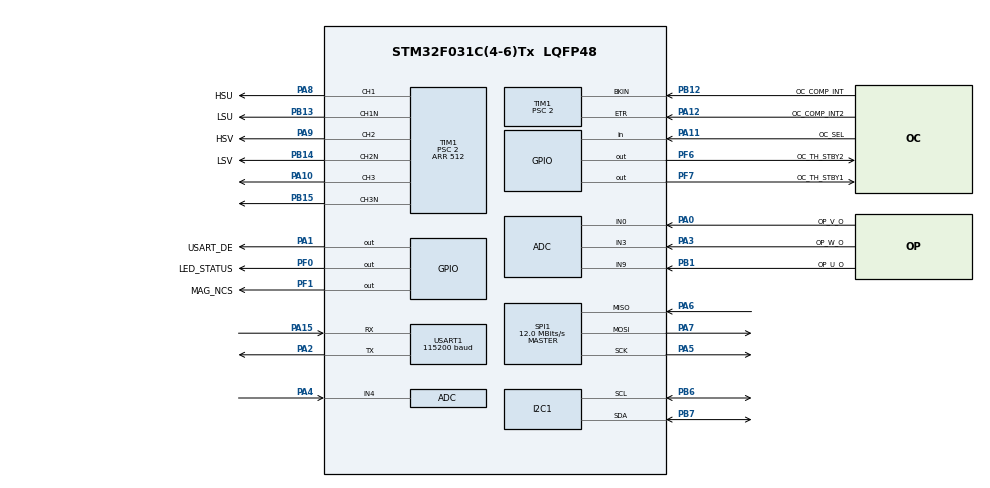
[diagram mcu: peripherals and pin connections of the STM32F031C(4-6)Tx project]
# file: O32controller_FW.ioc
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Dma.ADC.0.Direction=DMA_PERIPH_TO_MEMORY
Dma.ADC.0.Instance=DMA1_Channel1
Dma.ADC.0.MemDataAlignment=DMA_MDATAALIGN_HALFWORD
Dma.ADC.0.MemInc=DMA_MINC_ENABLE
Dma.ADC.0.Mode=DMA_CIRCULAR
Dma.ADC.0.PeriphDataAlignment=DMA_PDATAALIGN_HALFWORD
Dma.ADC.0.PeriphInc=DMA_PINC_DISABLE
Dma.ADC.0.Priority=DMA_PRIORITY_MEDIUM
Dma.Request0=ADC
Dma.Request1=USART1_TX
Dma.USART1_TX.1.Direction=DMA_MEMORY_TO_PERIPH
Dma.USART1_TX.1.Instance=DMA1_Channel4
Dma.USART1_TX.1.MemDataAlignment=DMA_MDATAALIGN_BYTE
Dma.USART1_TX.1.MemInc=DMA_MINC_ENABLE
Dma.USART1_TX.1.Mode=DMA_NORMAL
Dma.USART1_TX.1.PeriphDataAlignment=DMA_PDATAALIGN_BYTE
Dma.USART1_TX.1.PeriphInc=DMA_PINC_DISABLE
Dma.USART1_TX.1.Priority=DMA_PRIORITY_LOW
I2C1.NoStretchMode=I2C_NOSTRETCH_DISABLE
I2C1.OwnAddress=9
Mcu.Family=STM32F0
Mcu.Name=STM32F031C(4-6)Tx
Mcu.Package=LQFP48
NVIC.DMA1_Channel1_IRQn=true\:0\:0\:false\:false\:true\:false\:true\:true
NVIC.DMA1_Channel4_5_IRQn=true\:0\:0\:false\:false\:true\:false\:true\:true
NVIC.I2C1_IRQn=true\:0\:0\:false\:false\:true\:true\:true\:true
NVIC.SPI1_IRQn=true\:0\:0\:false\:false\:true\:true\:true\:true
NVIC.TIM2_IRQn=true\:0\:0\:false\:false\:true\:true\:true\:true
NVIC.USART1_IRQn=true\:0\:0\:false\:false\:true\:true\:true\:true
PA0.GPIO_Label=OP_V_O
PA0.Mode=IN0
PA0.Signal=ADC_IN0
PA1.GPIO_Label=USART_DE
PA1.GPIO_PuPd=GPIO_PULLDOWN
PA1.Signal=GPIO_Output
PA10.Signal=S_TIM1_CH3
PA11.GPIO_Label=OC_SEL
PA11.Signal=GPIO_Input
PA12.GPIO_Label=OC_COMP_INT2
PA12.Signal=S_TIM1_ETR
PA13.Mode=Serial_Wire
PA13.Signal=SYS_SWDIO
PA14.Mode=Serial_Wire
PA14.Signal=SYS_SWCLK
PA15.Mode=Asynchronous
PA15.Signal=USART1_RX
PA2.Mode=Asynchronous
PA2.Signal=USART1_TX
PA3.GPIO_Label=OP_W_O
PA3.Signal=SharedAnalog_PA3
PA4.Mode=IN4
PA4.Signal=ADC_IN4
PA5.Mode=Full_Duplex_Master
PA5.Signal=SPI1_SCK
PA6.Mode=Full_Duplex_Master
PA6.Signal=SPI1_MISO
PA7.Mode=Full_Duplex_Master
PA7.Signal=SPI1_MOSI
PA8.GPIO_Label=HSU
PA8.Signal=S_TIM1_CH1
PA9.GPIO_Label=HSV
PA9.Signal=S_TIM1_CH2
PB1.GPIO_Label=OP_U_O
PB1.Signal=SharedAnalog_PB1
PB12.GPIO_Label=OC_COMP_INT
PB12.Mode=Activate-Break-Input
PB12.Signal=TIM1_BKIN
PB13.GPIO_Label=LSU
PB13.Mode=PWM Generation1 CH1 CH1N
PB13.Signal=TIM1_CH1N
PB14.GPIO_Label=LSV
PB14.Mode=PWM Generation2 CH2 CH2N
PB14.Signal=TIM1_CH2N
PB15.Mode=PWM Generation3 CH3 CH3N
PB15.Signal=TIM1_CH3N
PB6.Mode=I2C
PB6.Signal=I2C1_SCL
PB7.Mode=I2C
PB7.Signal=I2C1_SDA
PF0-OSC_IN.GPIO_Label=LED_STATUS
PF0-OSC_IN.Signal=GPIO_Output
PF1-OSC_OUT.GPIO_Label=MAG_NCS
PF1-OSC_OUT.Signal=GPIO_Output
PF6.GPIO_Label=OC_TH_STBY2
PF6.Signal=GPIO_Output
PF7.GPIO_Label=OC_TH_STBY1
PF7.Signal=GPIO_Output
ProjectManager.HeapSize=0x200
ProjectManager.StackSize=0x400
ProjectManager.TargetToolchain=STM32CubeIDE
RCC.AHBFreq_Value=48000000
RCC.APB1Freq_Value=48000000
RCC.APB1TimFreq_Value=48000000
RCC.HCLKFreq_Value=48000000
RCC.PLLMUL=RCC_PLL_MUL12
RCC.SYSCLKFreq_VALUE=48000000
RCC.SYSCLKSource=RCC_SYSCLKSOURCE_PLLCLK
SH.S_TIM1_CH1.0=TIM1_CH1,PWM Generation1 CH1 CH1N
SH.S_TIM1_CH2.0=TIM1_CH2,PWM Generation2 CH2 CH2N
SH.S_TIM1_CH3.0=TIM1_CH3,PWM Generation3 CH3 CH3N
SH.S_TIM1_ETR.0=TIM1_ETR,TriggerSource_ETR
SH.SharedAnalog_PA3.0=GPIO_Analog
SH.SharedAnalog_PA3.1=ADC_IN3,IN3
SH.SharedAnalog_PB1.0=GPIO_Analog
SH.SharedAnalog_PB1.1=ADC_IN9,IN9
SPI1.BaudRatePrescaler=SPI_BAUDRATEPRESCALER_4
SPI1.CLKPolarity=SPI_POLARITY_HIGH
SPI1.CalculateBaudRate=12.0 MBits/s
SPI1.DataSize=SPI_DATASIZE_8BIT
SPI1.Direction=SPI_DIRECTION_2LINES
SPI1.Mode=SPI_MODE_MASTER
SPI1.VirtualType=VM_MASTER
TIM1.BreakPolarity=TIM_BREAKPOLARITY_HIGH
TIM1.BreakState=TIM_BREAK_DISABLE
TIM1.Channel-PWM\ Generation1\ CH1\ CH1N=TIM_CHANNEL_1
TIM1.Channel-PWM\ Generation2\ CH2\ CH2N=TIM_CHANNEL_2
TIM1.Channel-PWM\ Generation3\ CH3\ CH3N=TIM_CHANNEL_3
TIM1.DeadTime=10
TIM1.OCIdleState_1=TIM_OCIDLESTATE_RESET
TIM1.OCNIdleState_1=TIM_OCNIDLESTATE_RESET
TIM1.OCNIdleState_2=TIM_OCNIDLESTATE_RESET
TIM1.OCNPolarity_1=TIM_OCNPOLARITY_HIGH
TIM1.OCNPolarity_2=TIM_OCNPOLARITY_HIGH
TIM1.OCPolarity_2=TIM_OCPOLARITY_HIGH
TIM1.Period=512
TIM1.Prescaler=2
TIM1.Pulse-PWM\ Generation1\ CH1\ CH1N=0
TIM1.Slave_TriggerPolarity=TIM_TRIGGERPOLARITY_INVERTED
TIM1.TIM_MasterOutputTrigger=TIM_TRGO_RESET
TIM1.TIM_MasterSlaveMode=TIM_MASTERSLAVEMODE_DISABLE
TIM2.Period=10000
TIM2.Prescaler=63
USART1.BaudRate=115200
USART1.VirtualMode-Asynchronous=VM_ASYNC
VP_ADC_TempSens_Input.Mode=IN-TempSens
VP_ADC_Vref_Input.Mode=IN-Vrefint
VP_TIM1_VS_ClockSourceINT.Mode=Internal
VP_TIM1_VS_ControllerModeGated.Mode=Gated Mode
VP_TIM2_VS_ClockSourceINT.Mode=Internal
board=custom

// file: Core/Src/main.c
/* USER CODE BEGIN Header */

/* USER CODE END Header */
#include "main.h"

/* USER CODE BEGIN Includes */
#include "global.h"

#include "sixstep.h"
#include "foc.h"
#include "encoder.h"

#include <stdio.h>

/* USER CODE END Includes */

ADC_HandleTypeDef hadc;
DMA_HandleTypeDef hdma_adc;

I2C_HandleTypeDef hi2c1;

SPI_HandleTypeDef hspi1;

TIM_HandleTypeDef htim1;
TIM_HandleTypeDef htim2;

UART_HandleTypeDef huart1;
DMA_HandleTypeDef hdma_usart1_tx;

/* USER CODE BEGIN PV */

PeripherialStruct p = {0};

/* USER CODE END PV */

void SystemClock_Config(void);
static void MX_GPIO_Init(void);
static void MX_DMA_Init(void);
static void MX_I2C1_Init(void);
static void MX_ADC_Init(void);
static void MX_SPI1_Init(void);
static void MX_TIM1_Init(void);
static void MX_USART1_UART_Init(void);
static void MX_TIM2_Init(void);
/* USER CODE BEGIN PFP */

// overrides printf
int __io_putchar(int ch) {
    HAL_UART_Transmit(&huart1, (uint8_t *)&ch, 1, HAL_MAX_DELAY);
    return ch;
}

/* USER CODE END PFP */

int main(void) {

    /* MCU Configuration--------------------------------------------------------*/

    /* Reset of all peripherals, Initializes the Flash interface and the Systick. */
    HAL_Init();

    /* Configure the system clock */
    SystemClock_Config();

    /* Initialize all configured peripherals */
    MX_GPIO_Init();
    MX_DMA_Init();
    HAL_Delay(10);
    MX_I2C1_Init();
    MX_ADC_Init();
    MX_SPI1_Init();
    MX_TIM1_Init();
    MX_USART1_UART_Init();
    MX_TIM2_Init();
    /* USER CODE BEGIN 2 */

    HAL_MultiProcessor_Init(&huart1, UART_ADDR, UART_WAKEUPMETHOD_ADDRESSMARK);
    HAL_MultiProcessorEx_AddressLength_Set(&huart1, UART_ADDRESS_DETECT_4B);

    HAL_MultiProcessor_EnableMuteMode(&huart1);
    HAL_MultiProcessor_EnterMuteMode(&huart1);

    DISABLE_DRIVE;
    RS485_SET_RX;

    switch(SELECTED_MODE){
        case SIXSTEP_MODE:
            sixstep_startup();
            break;
        case FOC_MODE:
            foc_startup();
            break;
        case ENCODER_MODE:
            encoder_startup();
            break;
        default:
            break;
    }

    /* USER CODE END 2 */

    /* Infinite loop */
    /* USER CODE BEGIN WHILE */

    while (1) {

        switch(SELECTED_MODE){
        case SIXSTEP_MODE:
            sixstep_loop();
            break;
        case FOC_MODE:
            foc_loop();
            break;
        case ENCODER_MODE:
            encoder_loop();
            break;
        default:
            break;
    }

    if(p.clock_1khz_flag){ //watchdog checks if UART has been updated
        p.clock_1khz_flag = 0;

        switch (SELECTED_MODE) {
        case SIXSTEP_MODE:
            sixstep_slowloop();
            break;
        case FOC_MODE:
            foc_slowloop();
            break;
        case ENCODER_MODE:
            break;
        default:
            break;
        }

        p.uart_watchdog++;
        if (p.uart_watchdog >= UART_WATCHDOG_MS) {
            p.uart_watchdog = UART_WATCHDOG_MS;
            DISABLE_DRIVE;
            LED_RED;
        }
    }

        /* USER CODE END WHILE */

    }
}

void SystemClock_Config(void) {
    RCC_OscInitTypeDef RCC_OscInitStruct = {0};
    RCC_ClkInitTypeDef RCC_ClkInitStruct = {0};
    RCC_PeriphCLKInitTypeDef PeriphClkInit = {0};

    /** Initializes the RCC Oscillators according to the specified parameters
     * in the RCC_OscInitTypeDef structure.
     */
    RCC_OscInitStruct.OscillatorType = RCC_OSCILLATORTYPE_HSI | RCC_OSCILLATORTYPE_HSI14;
    RCC_OscInitStruct.HSIState = RCC_HSI_ON;
    RCC_OscInitStruct.HSI14State = RCC_HSI14_ON;
    RCC_OscInitStruct.HSICalibrationValue = RCC_HSICALIBRATION_DEFAULT;
    RCC_OscInitStruct.HSI14CalibrationValue = 16;
    RCC_OscInitStruct.PLL.PLLState = RCC_PLL_ON;
    RCC_OscInitStruct.PLL.PLLSource = RCC_PLLSOURCE_HSI;
    RCC_OscInitStruct.PLL.PLLMUL = RCC_PLL_MUL16; // can do RCC_PLL_MUL16 for 64MHz clock speed (affects PWM)
    RCC_OscInitStruct.PLL.PREDIV = RCC_PREDIV_DIV1;
    if (HAL_RCC_OscConfig(&RCC_OscInitStruct) != HAL_OK) {
        Error_Handler();
    }

    /** Initializes the CPU, AHB and APB buses clocks
     */
    RCC_ClkInitStruct.ClockType = RCC_CLOCKTYPE_HCLK | RCC_CLOCKTYPE_SYSCLK | RCC_CLOCKTYPE_PCLK1;
    RCC_ClkInitStruct.SYSCLKSource = RCC_SYSCLKSOURCE_PLLCLK;
    RCC_ClkInitStruct.AHBCLKDivider = RCC_SYSCLK_DIV1;
    RCC_ClkInitStruct.APB1CLKDivider = RCC_HCLK_DIV1;

    if (HAL_RCC_ClockConfig(&RCC_ClkInitStruct, FLASH_LATENCY_1) != HAL_OK) {
        Error_Handler();
    }
    PeriphClkInit.PeriphClockSelection = RCC_PERIPHCLK_USART1 | RCC_PERIPHCLK_I2C1;
    PeriphClkInit.Usart1ClockSelection = RCC_USART1CLKSOURCE_PCLK1;
    PeriphClkInit.I2c1ClockSelection = RCC_I2C1CLKSOURCE_HSI;
    if (HAL_RCCEx_PeriphCLKConfig(&PeriphClkInit) != HAL_OK) {
        Error_Handler();
    }
}

static void MX_ADC_Init(void) {

    ADC_ChannelConfTypeDef sConfig = {0};

    /** Configure the global features of the ADC (Clock, Resolution, Data Alignment and number of conversion)
     */
    hadc.Instance = ADC1;
    hadc.Init.ClockPrescaler = ADC_CLOCK_ASYNC_DIV1;
    hadc.Init.Resolution = ADC_RESOLUTION_12B;
    hadc.Init.DataAlign = ADC_DATAALIGN_RIGHT;
    hadc.Init.ScanConvMode = ADC_SCAN_DIRECTION_FORWARD;
    // hadc.Init.EOCSelection = ADC_EOC_SINGLE_CONV;
    hadc.Init.EOCSelection = ADC_EOC_SEQ_CONV;

    hadc.Init.LowPowerAutoWait = DISABLE;
    hadc.Init.LowPowerAutoPowerOff = DISABLE;
    hadc.Init.ContinuousConvMode = DISABLE;
    hadc.Init.DiscontinuousConvMode = DISABLE;
    hadc.Init.ExternalTrigConv = ADC_SOFTWARE_START;
    // hadc.Init.ExternalTrigConv = ADC_EXTERNALTRIGCONV_T1_TRGO;
    // hadc.Init.ExternalTrigConvEdge = ADC_EXTERNALTRIGCONVEDGE_RISING;
    hadc.Init.DMAContinuousRequests = DISABLE;
    hadc.Init.Overrun = ADC_OVR_DATA_PRESERVED;
    if (HAL_ADC_Init(&hadc) != HAL_OK) {
        Error_Handler();
    }

    /** Configure for the selected ADC regular channel to be converted.
     */
    sConfig.Channel = ADC_CHANNEL_0;
    sConfig.Rank = ADC_RANK_CHANNEL_NUMBER;
    sConfig.SamplingTime = ADC_SAMPLETIME_1CYCLE_5;
    if (HAL_ADC_ConfigChannel(&hadc, &sConfig) != HAL_OK) {
        Error_Handler();
    }

    /** Configure for the selected ADC regular channel to be converted.
     */
    sConfig.Channel = ADC_CHANNEL_3;
    if (HAL_ADC_ConfigChannel(&hadc, &sConfig) != HAL_OK) {
        Error_Handler();
    }

    /** Configure for the selected ADC regular channel to be converted.
     */
    sConfig.Channel = ADC_CHANNEL_4;
    if (HAL_ADC_ConfigChannel(&hadc, &sConfig) != HAL_OK) {
        Error_Handler();
    }

    /** Configure for the selected ADC regular channel to be converted.
     */
    sConfig.Channel = ADC_CHANNEL_9;
    if (HAL_ADC_ConfigChannel(&hadc, &sConfig) != HAL_OK) {
        Error_Handler();
    }

    /** Configure for the selected ADC regular channel to be converted.
     */
    sConfig.Channel = ADC_CHANNEL_TEMPSENSOR;
    if (HAL_ADC_ConfigChannel(&hadc, &sConfig) != HAL_OK) {
        Error_Handler();
    }

    /** Configure for the selected ADC regular channel to be converted.
     */
    sConfig.Channel = ADC_CHANNEL_VREFINT;
    if (HAL_ADC_ConfigChannel(&hadc, &sConfig) != HAL_OK) {
        Error_Handler();
    }
}

static void MX_I2C1_Init(void) {

    hi2c1.Instance = I2C1;
    hi2c1.Init.Timing = 0x2000090E;
    hi2c1.Init.OwnAddress1 = 18;
    hi2c1.Init.AddressingMode = I2C_ADDRESSINGMODE_7BIT;
    hi2c1.Init.DualAddressMode = I2C_DUALADDRESS_DISABLE;
    hi2c1.Init.OwnAddress2 = 0;
    hi2c1.Init.OwnAddress2Masks = I2C_OA2_NOMASK;
    hi2c1.Init.GeneralCallMode = I2C_GENERALCALL_DISABLE;
    hi2c1.Init.NoStretchMode = I2C_NOSTRETCH_DISABLE;
    if (HAL_I2C_Init(&hi2c1) != HAL_OK) {
        Error_Handler();
    }

    /** Configure Analogue filter
     */
    if (HAL_I2CEx_ConfigAnalogFilter(&hi2c1, I2C_ANALOGFILTER_ENABLE) != HAL_OK) {
        Error_Handler();
    }

    /** Configure Digital filter
     */
    if (HAL_I2CEx_ConfigDigitalFilter(&hi2c1, 0) != HAL_OK) {
        Error_Handler();
    }
}

static void MX_SPI1_Init(void) {

    /* SPI1 parameter configuration*/
    hspi1.Instance = SPI1;
    hspi1.Init.Mode = SPI_MODE_MASTER;
    hspi1.Init.Direction = SPI_DIRECTION_2LINES;
    hspi1.Init.DataSize = SPI_DATASIZE_8BIT;
    hspi1.Init.CLKPolarity = SPI_POLARITY_HIGH;
    hspi1.Init.CLKPhase = SPI_PHASE_1EDGE;
    hspi1.Init.NSS = SPI_NSS_SOFT;
    hspi1.Init.BaudRatePrescaler = SPI_BAUDRATEPRESCALER_4;
    hspi1.Init.FirstBit = SPI_FIRSTBIT_MSB;
    hspi1.Init.TIMode = SPI_TIMODE_DISABLE;
    hspi1.Init.CRCCalculation = SPI_CRCCALCULATION_DISABLE;
    hspi1.Init.CRCPolynomial = 7;
    hspi1.Init.CRCLength = SPI_CRC_LENGTH_DATASIZE;
    hspi1.Init.NSSPMode = SPI_NSS_PULSE_ENABLE;
    if (HAL_SPI_Init(&hspi1) != HAL_OK) {
        Error_Handler();
    }
}

static void MX_TIM1_Init(void) {

    TIM_ClockConfigTypeDef sClockSourceConfig = {0};
    TIM_SlaveConfigTypeDef sSlaveConfig = {0};
    TIM_MasterConfigTypeDef sMasterConfig = {0};
    TIM_OC_InitTypeDef sConfigOC = {0};
    TIM_BreakDeadTimeConfigTypeDef sBreakDeadTimeConfig = {0};

    htim1.Instance = TIM1;
    htim1.Init.Prescaler = 0;
    htim1.Init.CounterMode = TIM_COUNTERMODE_CENTERALIGNED1;
    htim1.Init.Period = MAX_DUTY;
    htim1.Init.ClockDivision = TIM_CLOCKDIVISION_DIV1;
    htim1.Init.RepetitionCounter = 0; // start with 0, then set RCR1 to create update event every other time on low edge
    htim1.Init.AutoReloadPreload = TIM_AUTORELOAD_PRELOAD_DISABLE;
    if (HAL_TIM_Base_Init(&htim1) != HAL_OK) {
        Error_Handler();
    }
    sClockSourceConfig.ClockSource = TIM_CLOCKSOURCE_INTERNAL;
    if (HAL_TIM_ConfigClockSource(&htim1, &sClockSourceConfig) != HAL_OK) {
        Error_Handler();
    }
    if (HAL_TIM_PWM_Init(&htim1) != HAL_OK) {
        Error_Handler();
    }
    sSlaveConfig.SlaveMode = TIM_SLAVEMODE_GATED;
    sSlaveConfig.InputTrigger = TIM_TS_ETRF;
    sSlaveConfig.TriggerPolarity = TIM_TRIGGERPOLARITY_INVERTED;
    sSlaveConfig.TriggerPrescaler = TIM_TRIGGERPRESCALER_DIV1;
    sSlaveConfig.TriggerFilter = 0;
    if (HAL_TIM_SlaveConfigSynchro(&htim1, &sSlaveConfig) != HAL_OK) {
        Error_Handler();
    }
    sMasterConfig.MasterOutputTrigger = TIM_TRGO_RESET;
    sMasterConfig.MasterSlaveMode = TIM_MASTERSLAVEMODE_DISABLE;
    if (HAL_TIMEx_MasterConfigSynchronization(&htim1, &sMasterConfig) != HAL_OK) {
        Error_Handler();
    }
    sConfigOC.OCMode = TIM_OCMODE_PWM1;
    sConfigOC.Pulse = 0;
    sConfigOC.OCPolarity = TIM_OCPOLARITY_HIGH;
    sConfigOC.OCNPolarity = TIM_OCNPOLARITY_HIGH;
    sConfigOC.OCFastMode = TIM_OCFAST_DISABLE;
    sConfigOC.OCIdleState = TIM_OCIDLESTATE_RESET;
    sConfigOC.OCNIdleState = TIM_OCNIDLESTATE_RESET;
    if (HAL_TIM_PWM_ConfigChannel(&htim1, &sConfigOC, TIM_CHANNEL_1) != HAL_OK) {
        Error_Handler();
    }
    if (HAL_TIM_PWM_ConfigChannel(&htim1, &sConfigOC, TIM_CHANNEL_2) != HAL_OK) {
        Error_Handler();
    }
    if (HAL_TIM_PWM_ConfigChannel(&htim1, &sConfigOC, TIM_CHANNEL_3) != HAL_OK) {
        Error_Handler();
    }
    sBreakDeadTimeConfig.OffStateRunMode = TIM_OSSR_DISABLE;
    sBreakDeadTimeConfig.OffStateIDLEMode = TIM_OSSI_DISABLE;
    sBreakDeadTimeConfig.LockLevel = TIM_LOCKLEVEL_OFF;
    sBreakDeadTimeConfig.DeadTime = 25;
    sBreakDeadTimeConfig.BreakState = TIM_BREAK_DISABLE;
    sBreakDeadTimeConfig.BreakPolarity = TIM_BREAKPOLARITY_HIGH;
    sBreakDeadTimeConfig.AutomaticOutput = TIM_AUTOMATICOUTPUT_DISABLE;
    if (HAL_TIMEx_ConfigBreakDeadTime(&htim1, &sBreakDeadTimeConfig) != HAL_OK) {
        Error_Handler();
    }
    /* USER CODE BEGIN TIM1_Init 2 */

    HAL_TIM_Base_Start_IT(&htim1); // Start TIM1 and enable the update interrupt

    HAL_NVIC_SetPriority(TIM1_BRK_UP_TRG_COM_IRQn, 0, 0); // Set the priority for TIM1 global interrupt
    HAL_NVIC_EnableIRQ(TIM1_BRK_UP_TRG_COM_IRQn); // Enable the TIM1 global interrupt

    /* USER CODE END TIM1_Init 2 */
    HAL_TIM_MspPostInit(&htim1);
}

static void MX_TIM2_Init(void) {

    TIM_ClockConfigTypeDef sClockSourceConfig = {0};
    TIM_MasterConfigTypeDef sMasterConfig = {0};

    htim2.Instance = TIM2;
    htim2.Init.Prescaler = 63;
    htim2.Init.CounterMode = TIM_COUNTERMODE_UP;
    htim2.Init.Period = 999; //100hz clock
    htim2.Init.ClockDivision = TIM_CLOCKDIVISION_DIV1;
    htim2.Init.AutoReloadPreload = TIM_AUTORELOAD_PRELOAD_DISABLE;
    if (HAL_TIM_Base_Init(&htim2) != HAL_OK) {
        Error_Handler();
    }
    sClockSourceConfig.ClockSource = TIM_CLOCKSOURCE_INTERNAL;
    if (HAL_TIM_ConfigClockSource(&htim2, &sClockSourceConfig) != HAL_OK) {
        Error_Handler();
    }
    sMasterConfig.MasterOutputTrigger = TIM_TRGO_RESET;
    sMasterConfig.MasterSlaveMode = TIM_MASTERSLAVEMODE_DISABLE;
    if (HAL_TIMEx_MasterConfigSynchronization(&htim2, &sMasterConfig) != HAL_OK) {
        Error_Handler();
    }
}

static void MX_USART1_UART_Init(void) {

    huart1.Instance = USART1;
    huart1.Init.BaudRate = 1000000;
    huart1.Init.WordLength = UART_WORDLENGTH_8B;
    huart1.Init.StopBits = UART_STOPBITS_1;
    huart1.Init.Parity = UART_PARITY_NONE;
    huart1.Init.Mode = UART_MODE_TX_RX;
    huart1.Init.HwFlowCtl = UART_HWCONTROL_NONE;
    huart1.Init.OverSampling = UART_OVERSAMPLING_16;
    huart1.Init.OneBitSampling = UART_ONE_BIT_SAMPLE_DISABLE;
    huart1.AdvancedInit.AdvFeatureInit = UART_ADVFEATURE_NO_INIT;
    if (HAL_UART_Init(&huart1) != HAL_OK) {
        Error_Handler();
    }
    /* USER CODE BEGIN USART1_Init 2 */

    // __HAL_UART_ENABLE_IT(&huart1, UART_IT_IDLE); // enable idle line interrupt

    /* USER CODE END USART1_Init 2 */
}

static void MX_DMA_Init(void) {

    /* DMA controller clock enable */
    __HAL_RCC_DMA1_CLK_ENABLE();

    /* DMA interrupt init */
    /* DMA1_Channel1_IRQn interrupt configuration */
    HAL_NVIC_SetPriority(DMA1_Channel1_IRQn, 0, 0);
    HAL_NVIC_EnableIRQ(DMA1_Channel1_IRQn);
    /* DMA1_Channel4_5_IRQn interrupt configuration */
    HAL_NVIC_SetPriority(DMA1_Channel4_5_IRQn, 0, 0);
    HAL_NVIC_EnableIRQ(DMA1_Channel4_5_IRQn);
}

static void MX_GPIO_Init(void) {
    GPIO_InitTypeDef GPIO_InitStruct = {0};

    /* GPIO Ports Clock Enable */
    __HAL_RCC_GPIOF_CLK_ENABLE();
    __HAL_RCC_GPIOA_CLK_ENABLE();
    __HAL_RCC_GPIOB_CLK_ENABLE();

    /*Configure GPIO pin Output Level */
    HAL_GPIO_WritePin(GPIOF, LED_STATUS_Pin | MAG_NCS_Pin | OC_TH_STBY2_Pin | OC_TH_STBY1_Pin, GPIO_PIN_RESET);

    /*Configure GPIO pin Output Level */
    HAL_GPIO_WritePin(USART_DE_GPIO_Port, USART_DE_Pin, GPIO_PIN_RESET);

    /*Configure GPIO pins : LED_STATUS_Pin MAG_NCS_Pin OC_TH_STBY2_Pin OC_TH_STBY1_Pin */
    GPIO_InitStruct.Pin = LED_STATUS_Pin | MAG_NCS_Pin | OC_TH_STBY2_Pin | OC_TH_STBY1_Pin;
    GPIO_InitStruct.Mode = GPIO_MODE_OUTPUT_PP;
    GPIO_InitStruct.Pull = GPIO_NOPULL;
    GPIO_InitStruct.Speed = GPIO_SPEED_FREQ_LOW;
    HAL_GPIO_Init(GPIOF, &GPIO_InitStruct);

    /*Configure GPIO pin : USART_DE_Pin */
    GPIO_InitStruct.Pin = USART_DE_Pin;
    GPIO_InitStruct.Mode = GPIO_MODE_OUTPUT_PP;
    GPIO_InitStruct.Pull = GPIO_PULLDOWN;
    GPIO_InitStruct.Speed = GPIO_SPEED_FREQ_LOW;
    HAL_GPIO_Init(USART_DE_GPIO_Port, &GPIO_InitStruct);

    /*Configure GPIO pin : OC_SEL_Pin */
    GPIO_InitStruct.Pin = OC_SEL_Pin;
    GPIO_InitStruct.Mode = GPIO_MODE_INPUT;
    GPIO_InitStruct.Pull = GPIO_NOPULL;
    HAL_GPIO_Init(OC_SEL_GPIO_Port, &GPIO_InitStruct);

}

/* USER CODE BEGIN 4 */

// Callback whenever a timer rolls over
void HAL_TIM_PeriodElapsedCallback(TIM_HandleTypeDef *htim) {
    if (htim == &htim2) { // 100Hz
        p.clock_1khz_flag = 1;
    }
}

void HAL_UARTEx_RxEventCallback(UART_HandleTypeDef *huart, uint16_t Size) {
    if(Size != UART_RX_SIZE){
        RS485_SET_RX;
        HAL_UARTEx_ReceiveToIdle_IT(&huart1, p.uart_RX, UART_RX_SIZE);
        return;
    }
    p.uart_received_flag = 1; //commutation loop will read and clear

    if(p.uart_watchdog >= UART_WATCHDOG_MS){ //if watchdog has disabled motor, enable it again
       ENABLE_DRIVE;
    }

//    RS485_SET_TX;
//    HAL_UART_Transmit_DMA(&huart1, p.uart_TX, 9);

//    HAL_UARTEx_ReceiveToIdle_IT(&huart1, p.uart_RX, UART_RX_SIZE);
    p.uart_watchdog = 0; //resets watchdog
}

void HAL_UART_TxCpltCallback(UART_HandleTypeDef *huart) {
    RS485_SET_RX;
    HAL_UARTEx_ReceiveToIdle_IT(&huart1, p.uart_RX, UART_RX_SIZE);
}

void HAL_UART_ErrorCallback(UART_HandleTypeDef *huart) { // shouldn't happen but just in case of overrun, restart RX

    volatile uint32_t errorcode = huart->ErrorCode;

    // clear the uart buffer
    uint8_t temp_buffer[100];
    while (__HAL_UART_GET_FLAG(&huart1, UART_FLAG_RXNE)) {
        HAL_UART_Receive(&huart1, temp_buffer, 1, 1);
    }

    RS485_SET_RX;
    HAL_UARTEx_ReceiveToIdle_IT(&huart1, p.uart_RX, UART_RX_SIZE);

    LED_RED;
}

void HAL_ADC_ConvCpltCallback(ADC_HandleTypeDef* hadc) {
    if (hadc->Instance == ADC1) {
        // End of conversion actions
//        LED_GREEN;
        p.adc_conversion_flag = 1; //allow main loop to continiue
    }
}

/* USER CODE END 4 */

void Error_Handler(void) {
    /* USER CODE BEGIN Error_Handler_Debug */
    /* User can add his own implementation to report the HAL error return state */
    LED_RED;
    printf("ERROR HANDLER \n");
    __disable_irq();    // disable interrupts
    NVIC_SystemReset(); // reset microcontroller, clearing any I2C faults. Maybe change to only
                        // reinit the I2C to save power.
    while (1) {
    } // if reset takes a while, do nothing

    /* USER CODE END Error_Handler_Debug */
}
